VERSION 5.7 ;
BUSBITCHARS "[]" ;
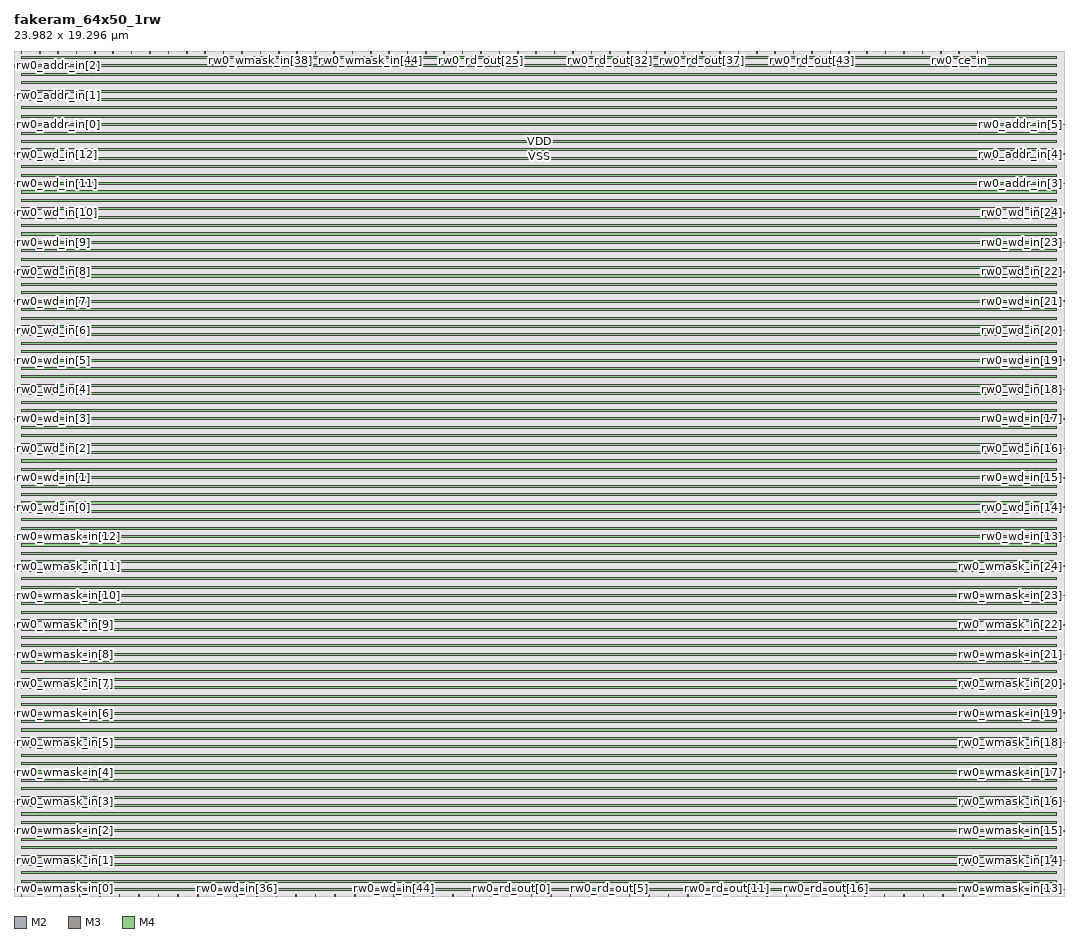
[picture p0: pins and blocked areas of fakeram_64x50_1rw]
MACRO fakeram_64x50_1rw
  FOREIGN fakeram_64x50_1rw 0 0 ;
  SYMMETRY X Y R90 ;
  SIZE 23.982 BY 19.296 ;
  CLASS BLOCK ;
  PIN rw0_wmask_in[0]
    DIRECTION INPUT ;
    USE SIGNAL ;
    SHAPE ABUTMENT ;
    PORT
      LAYER M2 ;
      RECT 0.000 0.138 0.036 0.150 ;
    END
  END rw0_wmask_in[0]
  PIN rw0_wmask_in[1]
    DIRECTION INPUT ;
    USE SIGNAL ;
    SHAPE ABUTMENT ;
    PORT
      LAYER M2 ;
      RECT 0.000 0.810 0.036 0.822 ;
    END
  END rw0_wmask_in[1]
  PIN rw0_wmask_in[2]
    DIRECTION INPUT ;
    USE SIGNAL ;
    SHAPE ABUTMENT ;
    PORT
      LAYER M2 ;
      RECT 0.000 1.482 0.036 1.494 ;
    END
  END rw0_wmask_in[2]
  PIN rw0_wmask_in[3]
    DIRECTION INPUT ;
    USE SIGNAL ;
    SHAPE ABUTMENT ;
    PORT
      LAYER M2 ;
      RECT 0.000 2.154 0.036 2.166 ;
    END
  END rw0_wmask_in[3]
  PIN rw0_wmask_in[4]
    DIRECTION INPUT ;
    USE SIGNAL ;
    SHAPE ABUTMENT ;
    PORT
      LAYER M2 ;
      RECT 0.000 2.826 0.036 2.838 ;
    END
  END rw0_wmask_in[4]
  PIN rw0_wmask_in[5]
    DIRECTION INPUT ;
    USE SIGNAL ;
    SHAPE ABUTMENT ;
    PORT
      LAYER M2 ;
      RECT 0.000 3.498 0.036 3.510 ;
    END
  END rw0_wmask_in[5]
  PIN rw0_wmask_in[6]
    DIRECTION INPUT ;
    USE SIGNAL ;
    SHAPE ABUTMENT ;
    PORT
      LAYER M2 ;
      RECT 0.000 4.170 0.036 4.182 ;
    END
  END rw0_wmask_in[6]
  PIN rw0_wmask_in[7]
    DIRECTION INPUT ;
    USE SIGNAL ;
    SHAPE ABUTMENT ;
    PORT
      LAYER M2 ;
      RECT 0.000 4.842 0.036 4.854 ;
    END
  END rw0_wmask_in[7]
  PIN rw0_wmask_in[8]
    DIRECTION INPUT ;
    USE SIGNAL ;
    SHAPE ABUTMENT ;
    PORT
      LAYER M2 ;
      RECT 0.000 5.514 0.036 5.526 ;
    END
  END rw0_wmask_in[8]
  PIN rw0_wmask_in[9]
    DIRECTION INPUT ;
    USE SIGNAL ;
    SHAPE ABUTMENT ;
    PORT
      LAYER M2 ;
      RECT 0.000 6.186 0.036 6.198 ;
    END
  END rw0_wmask_in[9]
  PIN rw0_wmask_in[10]
    DIRECTION INPUT ;
    USE SIGNAL ;
    SHAPE ABUTMENT ;
    PORT
      LAYER M2 ;
      RECT 0.000 6.858 0.036 6.870 ;
    END
  END rw0_wmask_in[10]
  PIN rw0_wmask_in[11]
    DIRECTION INPUT ;
    USE SIGNAL ;
    SHAPE ABUTMENT ;
    PORT
      LAYER M2 ;
      RECT 0.000 7.530 0.036 7.542 ;
    END
  END rw0_wmask_in[11]
  PIN rw0_wmask_in[12]
    DIRECTION INPUT ;
    USE SIGNAL ;
    SHAPE ABUTMENT ;
    PORT
      LAYER M2 ;
      RECT 0.000 8.202 0.036 8.214 ;
    END
  END rw0_wmask_in[12]
  PIN rw0_wmask_in[13]
    DIRECTION INPUT ;
    USE SIGNAL ;
    SHAPE ABUTMENT ;
    PORT
      LAYER M2 ;
      RECT 23.946 0.138 23.982 0.150 ;
    END
  END rw0_wmask_in[13]
  PIN rw0_wmask_in[14]
    DIRECTION INPUT ;
    USE SIGNAL ;
    SHAPE ABUTMENT ;
    PORT
      LAYER M2 ;
      RECT 23.946 0.810 23.982 0.822 ;
    END
  END rw0_wmask_in[14]
  PIN rw0_wmask_in[15]
    DIRECTION INPUT ;
    USE SIGNAL ;
    SHAPE ABUTMENT ;
    PORT
      LAYER M2 ;
      RECT 23.946 1.482 23.982 1.494 ;
    END
  END rw0_wmask_in[15]
  PIN rw0_wmask_in[16]
    DIRECTION INPUT ;
    USE SIGNAL ;
    SHAPE ABUTMENT ;
    PORT
      LAYER M2 ;
      RECT 23.946 2.154 23.982 2.166 ;
    END
  END rw0_wmask_in[16]
  PIN rw0_wmask_in[17]
    DIRECTION INPUT ;
    USE SIGNAL ;
    SHAPE ABUTMENT ;
    PORT
      LAYER M2 ;
      RECT 23.946 2.826 23.982 2.838 ;
    END
  END rw0_wmask_in[17]
  PIN rw0_wmask_in[18]
    DIRECTION INPUT ;
    USE SIGNAL ;
    SHAPE ABUTMENT ;
    PORT
      LAYER M2 ;
      RECT 23.946 3.498 23.982 3.510 ;
    END
  END rw0_wmask_in[18]
  PIN rw0_wmask_in[19]
    DIRECTION INPUT ;
    USE SIGNAL ;
    SHAPE ABUTMENT ;
    PORT
      LAYER M2 ;
      RECT 23.946 4.170 23.982 4.182 ;
    END
  END rw0_wmask_in[19]
  PIN rw0_wmask_in[20]
    DIRECTION INPUT ;
    USE SIGNAL ;
    SHAPE ABUTMENT ;
    PORT
      LAYER M2 ;
      RECT 23.946 4.842 23.982 4.854 ;
    END
  END rw0_wmask_in[20]
  PIN rw0_wmask_in[21]
    DIRECTION INPUT ;
    USE SIGNAL ;
    SHAPE ABUTMENT ;
    PORT
      LAYER M2 ;
      RECT 23.946 5.514 23.982 5.526 ;
    END
  END rw0_wmask_in[21]
  PIN rw0_wmask_in[22]
    DIRECTION INPUT ;
    USE SIGNAL ;
    SHAPE ABUTMENT ;
    PORT
      LAYER M2 ;
      RECT 23.946 6.186 23.982 6.198 ;
    END
  END rw0_wmask_in[22]
  PIN rw0_wmask_in[23]
    DIRECTION INPUT ;
    USE SIGNAL ;
    SHAPE ABUTMENT ;
    PORT
      LAYER M2 ;
      RECT 23.946 6.858 23.982 6.870 ;
    END
  END rw0_wmask_in[23]
  PIN rw0_wmask_in[24]
    DIRECTION INPUT ;
    USE SIGNAL ;
    SHAPE ABUTMENT ;
    PORT
      LAYER M2 ;
      RECT 23.946 7.530 23.982 7.542 ;
    END
  END rw0_wmask_in[24]
  PIN rw0_wmask_in[25]
    DIRECTION INPUT ;
    USE SIGNAL ;
    SHAPE ABUTMENT ;
    PORT
      LAYER M3 ;
      RECT 0.161 19.254 0.175 19.296 ;
    END
  END rw0_wmask_in[25]
  PIN rw0_wmask_in[26]
    DIRECTION INPUT ;
    USE SIGNAL ;
    SHAPE ABUTMENT ;
    PORT
      LAYER M3 ;
      RECT 0.581 19.254 0.595 19.296 ;
    END
  END rw0_wmask_in[26]
  PIN rw0_wmask_in[27]
    DIRECTION INPUT ;
    USE SIGNAL ;
    SHAPE ABUTMENT ;
    PORT
      LAYER M3 ;
      RECT 1.001 19.254 1.015 19.296 ;
    END
  END rw0_wmask_in[27]
  PIN rw0_wmask_in[28]
    DIRECTION INPUT ;
    USE SIGNAL ;
    SHAPE ABUTMENT ;
    PORT
      LAYER M3 ;
      RECT 1.421 19.254 1.435 19.296 ;
    END
  END rw0_wmask_in[28]
  PIN rw0_wmask_in[29]
    DIRECTION INPUT ;
    USE SIGNAL ;
    SHAPE ABUTMENT ;
    PORT
      LAYER M3 ;
      RECT 1.841 19.254 1.855 19.296 ;
    END
  END rw0_wmask_in[29]
  PIN rw0_wmask_in[30]
    DIRECTION INPUT ;
    USE SIGNAL ;
    SHAPE ABUTMENT ;
    PORT
      LAYER M3 ;
      RECT 2.261 19.254 2.275 19.296 ;
    END
  END rw0_wmask_in[30]
  PIN rw0_wmask_in[31]
    DIRECTION INPUT ;
    USE SIGNAL ;
    SHAPE ABUTMENT ;
    PORT
      LAYER M3 ;
      RECT 2.681 19.254 2.695 19.296 ;
    END
  END rw0_wmask_in[31]
  PIN rw0_wmask_in[32]
    DIRECTION INPUT ;
    USE SIGNAL ;
    SHAPE ABUTMENT ;
    PORT
      LAYER M3 ;
      RECT 3.101 19.254 3.115 19.296 ;
    END
  END rw0_wmask_in[32]
  PIN rw0_wmask_in[33]
    DIRECTION INPUT ;
    USE SIGNAL ;
    SHAPE ABUTMENT ;
    PORT
      LAYER M3 ;
      RECT 3.521 19.254 3.535 19.296 ;
    END
  END rw0_wmask_in[33]
  PIN rw0_wmask_in[34]
    DIRECTION INPUT ;
    USE SIGNAL ;
    SHAPE ABUTMENT ;
    PORT
      LAYER M3 ;
      RECT 3.941 19.254 3.955 19.296 ;
    END
  END rw0_wmask_in[34]
  PIN rw0_wmask_in[35]
    DIRECTION INPUT ;
    USE SIGNAL ;
    SHAPE ABUTMENT ;
    PORT
      LAYER M3 ;
      RECT 4.361 19.254 4.375 19.296 ;
    END
  END rw0_wmask_in[35]
  PIN rw0_wmask_in[36]
    DIRECTION INPUT ;
    USE SIGNAL ;
    SHAPE ABUTMENT ;
    PORT
      LAYER M3 ;
      RECT 4.781 19.254 4.795 19.296 ;
    END
  END rw0_wmask_in[36]
  PIN rw0_wmask_in[37]
    DIRECTION INPUT ;
    USE SIGNAL ;
    SHAPE ABUTMENT ;
    PORT
      LAYER M3 ;
      RECT 5.201 19.254 5.215 19.296 ;
    END
  END rw0_wmask_in[37]
  PIN rw0_wmask_in[38]
    DIRECTION INPUT ;
    USE SIGNAL ;
    SHAPE ABUTMENT ;
    PORT
      LAYER M3 ;
      RECT 5.621 19.254 5.635 19.296 ;
    END
  END rw0_wmask_in[38]
  PIN rw0_wmask_in[39]
    DIRECTION INPUT ;
    USE SIGNAL ;
    SHAPE ABUTMENT ;
    PORT
      LAYER M3 ;
      RECT 6.041 19.254 6.055 19.296 ;
    END
  END rw0_wmask_in[39]
  PIN rw0_wmask_in[40]
    DIRECTION INPUT ;
    USE SIGNAL ;
    SHAPE ABUTMENT ;
    PORT
      LAYER M3 ;
      RECT 6.461 19.254 6.475 19.296 ;
    END
  END rw0_wmask_in[40]
  PIN rw0_wmask_in[41]
    DIRECTION INPUT ;
    USE SIGNAL ;
    SHAPE ABUTMENT ;
    PORT
      LAYER M3 ;
      RECT 6.881 19.254 6.895 19.296 ;
    END
  END rw0_wmask_in[41]
  PIN rw0_wmask_in[42]
    DIRECTION INPUT ;
    USE SIGNAL ;
    SHAPE ABUTMENT ;
    PORT
      LAYER M3 ;
      RECT 7.301 19.254 7.315 19.296 ;
    END
  END rw0_wmask_in[42]
  PIN rw0_wmask_in[43]
    DIRECTION INPUT ;
    USE SIGNAL ;
    SHAPE ABUTMENT ;
    PORT
      LAYER M3 ;
      RECT 7.721 19.254 7.735 19.296 ;
    END
  END rw0_wmask_in[43]
  PIN rw0_wmask_in[44]
    DIRECTION INPUT ;
    USE SIGNAL ;
    SHAPE ABUTMENT ;
    PORT
      LAYER M3 ;
      RECT 8.141 19.254 8.155 19.296 ;
    END
  END rw0_wmask_in[44]
  PIN rw0_wmask_in[45]
    DIRECTION INPUT ;
    USE SIGNAL ;
    SHAPE ABUTMENT ;
    PORT
      LAYER M3 ;
      RECT 8.561 19.254 8.575 19.296 ;
    END
  END rw0_wmask_in[45]
  PIN rw0_wmask_in[46]
    DIRECTION INPUT ;
    USE SIGNAL ;
    SHAPE ABUTMENT ;
    PORT
      LAYER M3 ;
      RECT 8.981 19.254 8.995 19.296 ;
    END
  END rw0_wmask_in[46]
  PIN rw0_wmask_in[47]
    DIRECTION INPUT ;
    USE SIGNAL ;
    SHAPE ABUTMENT ;
    PORT
      LAYER M3 ;
      RECT 9.401 19.254 9.415 19.296 ;
    END
  END rw0_wmask_in[47]
  PIN rw0_wmask_in[48]
    DIRECTION INPUT ;
    USE SIGNAL ;
    SHAPE ABUTMENT ;
    PORT
      LAYER M3 ;
      RECT 9.821 19.254 9.835 19.296 ;
    END
  END rw0_wmask_in[48]
  PIN rw0_wmask_in[49]
    DIRECTION INPUT ;
    USE SIGNAL ;
    SHAPE ABUTMENT ;
    PORT
      LAYER M3 ;
      RECT 10.241 19.254 10.255 19.296 ;
    END
  END rw0_wmask_in[49]
  PIN rw0_wd_in[0]
    DIRECTION INPUT ;
    USE SIGNAL ;
    SHAPE ABUTMENT ;
    PORT
      LAYER M2 ;
      RECT 0.000 8.874 0.036 8.886 ;
    END
  END rw0_wd_in[0]
  PIN rw0_wd_in[1]
    DIRECTION INPUT ;
    USE SIGNAL ;
    SHAPE ABUTMENT ;
    PORT
      LAYER M2 ;
      RECT 0.000 9.546 0.036 9.558 ;
    END
  END rw0_wd_in[1]
  PIN rw0_wd_in[2]
    DIRECTION INPUT ;
    USE SIGNAL ;
    SHAPE ABUTMENT ;
    PORT
      LAYER M2 ;
      RECT 0.000 10.218 0.036 10.230 ;
    END
  END rw0_wd_in[2]
  PIN rw0_wd_in[3]
    DIRECTION INPUT ;
    USE SIGNAL ;
    SHAPE ABUTMENT ;
    PORT
      LAYER M2 ;
      RECT 0.000 10.890 0.036 10.902 ;
    END
  END rw0_wd_in[3]
  PIN rw0_wd_in[4]
    DIRECTION INPUT ;
    USE SIGNAL ;
    SHAPE ABUTMENT ;
    PORT
      LAYER M2 ;
      RECT 0.000 11.562 0.036 11.574 ;
    END
  END rw0_wd_in[4]
  PIN rw0_wd_in[5]
    DIRECTION INPUT ;
    USE SIGNAL ;
    SHAPE ABUTMENT ;
    PORT
      LAYER M2 ;
      RECT 0.000 12.234 0.036 12.246 ;
    END
  END rw0_wd_in[5]
  PIN rw0_wd_in[6]
    DIRECTION INPUT ;
    USE SIGNAL ;
    SHAPE ABUTMENT ;
    PORT
      LAYER M2 ;
      RECT 0.000 12.906 0.036 12.918 ;
    END
  END rw0_wd_in[6]
  PIN rw0_wd_in[7]
    DIRECTION INPUT ;
    USE SIGNAL ;
    SHAPE ABUTMENT ;
    PORT
      LAYER M2 ;
      RECT 0.000 13.578 0.036 13.590 ;
    END
  END rw0_wd_in[7]
  PIN rw0_wd_in[8]
    DIRECTION INPUT ;
    USE SIGNAL ;
    SHAPE ABUTMENT ;
    PORT
      LAYER M2 ;
      RECT 0.000 14.250 0.036 14.262 ;
    END
  END rw0_wd_in[8]
  PIN rw0_wd_in[9]
    DIRECTION INPUT ;
    USE SIGNAL ;
    SHAPE ABUTMENT ;
    PORT
      LAYER M2 ;
      RECT 0.000 14.922 0.036 14.934 ;
    END
  END rw0_wd_in[9]
  PIN rw0_wd_in[10]
    DIRECTION INPUT ;
    USE SIGNAL ;
    SHAPE ABUTMENT ;
    PORT
      LAYER M2 ;
      RECT 0.000 15.594 0.036 15.606 ;
    END
  END rw0_wd_in[10]
  PIN rw0_wd_in[11]
    DIRECTION INPUT ;
    USE SIGNAL ;
    SHAPE ABUTMENT ;
    PORT
      LAYER M2 ;
      RECT 0.000 16.266 0.036 16.278 ;
    END
  END rw0_wd_in[11]
  PIN rw0_wd_in[12]
    DIRECTION INPUT ;
    USE SIGNAL ;
    SHAPE ABUTMENT ;
    PORT
      LAYER M2 ;
      RECT 0.000 16.938 0.036 16.950 ;
    END
  END rw0_wd_in[12]
  PIN rw0_wd_in[13]
    DIRECTION INPUT ;
    USE SIGNAL ;
    SHAPE ABUTMENT ;
    PORT
      LAYER M2 ;
      RECT 23.946 8.202 23.982 8.214 ;
    END
  END rw0_wd_in[13]
  PIN rw0_wd_in[14]
    DIRECTION INPUT ;
    USE SIGNAL ;
    SHAPE ABUTMENT ;
    PORT
      LAYER M2 ;
      RECT 23.946 8.874 23.982 8.886 ;
    END
  END rw0_wd_in[14]
  PIN rw0_wd_in[15]
    DIRECTION INPUT ;
    USE SIGNAL ;
    SHAPE ABUTMENT ;
    PORT
      LAYER M2 ;
      RECT 23.946 9.546 23.982 9.558 ;
    END
  END rw0_wd_in[15]
  PIN rw0_wd_in[16]
    DIRECTION INPUT ;
    USE SIGNAL ;
    SHAPE ABUTMENT ;
    PORT
      LAYER M2 ;
      RECT 23.946 10.218 23.982 10.230 ;
    END
  END rw0_wd_in[16]
  PIN rw0_wd_in[17]
    DIRECTION INPUT ;
    USE SIGNAL ;
    SHAPE ABUTMENT ;
    PORT
      LAYER M2 ;
      RECT 23.946 10.890 23.982 10.902 ;
    END
  END rw0_wd_in[17]
  PIN rw0_wd_in[18]
    DIRECTION INPUT ;
    USE SIGNAL ;
    SHAPE ABUTMENT ;
    PORT
      LAYER M2 ;
      RECT 23.946 11.562 23.982 11.574 ;
    END
  END rw0_wd_in[18]
  PIN rw0_wd_in[19]
    DIRECTION INPUT ;
    USE SIGNAL ;
    SHAPE ABUTMENT ;
    PORT
      LAYER M2 ;
      RECT 23.946 12.234 23.982 12.246 ;
    END
  END rw0_wd_in[19]
  PIN rw0_wd_in[20]
    DIRECTION INPUT ;
    USE SIGNAL ;
    SHAPE ABUTMENT ;
    PORT
      LAYER M2 ;
      RECT 23.946 12.906 23.982 12.918 ;
    END
  END rw0_wd_in[20]
  PIN rw0_wd_in[21]
    DIRECTION INPUT ;
    USE SIGNAL ;
    SHAPE ABUTMENT ;
    PORT
      LAYER M2 ;
      RECT 23.946 13.578 23.982 13.590 ;
    END
  END rw0_wd_in[21]
  PIN rw0_wd_in[22]
    DIRECTION INPUT ;
    USE SIGNAL ;
    SHAPE ABUTMENT ;
    PORT
      LAYER M2 ;
      RECT 23.946 14.250 23.982 14.262 ;
    END
  END rw0_wd_in[22]
  PIN rw0_wd_in[23]
    DIRECTION INPUT ;
    USE SIGNAL ;
    SHAPE ABUTMENT ;
    PORT
      LAYER M2 ;
      RECT 23.946 14.922 23.982 14.934 ;
    END
  END rw0_wd_in[23]
  PIN rw0_wd_in[24]
    DIRECTION INPUT ;
    USE SIGNAL ;
    SHAPE ABUTMENT ;
    PORT
      LAYER M2 ;
      RECT 23.946 15.594 23.982 15.606 ;
    END
  END rw0_wd_in[24]
  PIN rw0_wd_in[25]
    DIRECTION INPUT ;
    USE SIGNAL ;
    SHAPE ABUTMENT ;
    PORT
      LAYER M3 ;
      RECT 0.161 0.000 0.175 0.042 ;
    END
  END rw0_wd_in[25]
  PIN rw0_wd_in[26]
    DIRECTION INPUT ;
    USE SIGNAL ;
    SHAPE ABUTMENT ;
    PORT
      LAYER M3 ;
      RECT 0.609 0.000 0.623 0.042 ;
    END
  END rw0_wd_in[26]
  PIN rw0_wd_in[27]
    DIRECTION INPUT ;
    USE SIGNAL ;
    SHAPE ABUTMENT ;
    PORT
      LAYER M3 ;
      RECT 1.057 0.000 1.071 0.042 ;
    END
  END rw0_wd_in[27]
  PIN rw0_wd_in[28]
    DIRECTION INPUT ;
    USE SIGNAL ;
    SHAPE ABUTMENT ;
    PORT
      LAYER M3 ;
      RECT 1.505 0.000 1.519 0.042 ;
    END
  END rw0_wd_in[28]
  PIN rw0_wd_in[29]
    DIRECTION INPUT ;
    USE SIGNAL ;
    SHAPE ABUTMENT ;
    PORT
      LAYER M3 ;
      RECT 1.953 0.000 1.967 0.042 ;
    END
  END rw0_wd_in[29]
  PIN rw0_wd_in[30]
    DIRECTION INPUT ;
    USE SIGNAL ;
    SHAPE ABUTMENT ;
    PORT
      LAYER M3 ;
      RECT 2.401 0.000 2.415 0.042 ;
    END
  END rw0_wd_in[30]
  PIN rw0_wd_in[31]
    DIRECTION INPUT ;
    USE SIGNAL ;
    SHAPE ABUTMENT ;
    PORT
      LAYER M3 ;
      RECT 2.849 0.000 2.863 0.042 ;
    END
  END rw0_wd_in[31]
  PIN rw0_wd_in[32]
    DIRECTION INPUT ;
    USE SIGNAL ;
    SHAPE ABUTMENT ;
    PORT
      LAYER M3 ;
      RECT 3.297 0.000 3.311 0.042 ;
    END
  END rw0_wd_in[32]
  PIN rw0_wd_in[33]
    DIRECTION INPUT ;
    USE SIGNAL ;
    SHAPE ABUTMENT ;
    PORT
      LAYER M3 ;
      RECT 3.745 0.000 3.759 0.042 ;
    END
  END rw0_wd_in[33]
  PIN rw0_wd_in[34]
    DIRECTION INPUT ;
    USE SIGNAL ;
    SHAPE ABUTMENT ;
    PORT
      LAYER M3 ;
      RECT 4.193 0.000 4.207 0.042 ;
    END
  END rw0_wd_in[34]
  PIN rw0_wd_in[35]
    DIRECTION INPUT ;
    USE SIGNAL ;
    SHAPE ABUTMENT ;
    PORT
      LAYER M3 ;
      RECT 4.641 0.000 4.655 0.042 ;
    END
  END rw0_wd_in[35]
  PIN rw0_wd_in[36]
    DIRECTION INPUT ;
    USE SIGNAL ;
    SHAPE ABUTMENT ;
    PORT
      LAYER M3 ;
      RECT 5.089 0.000 5.103 0.042 ;
    END
  END rw0_wd_in[36]
  PIN rw0_wd_in[37]
    DIRECTION INPUT ;
    USE SIGNAL ;
    SHAPE ABUTMENT ;
    PORT
      LAYER M3 ;
      RECT 5.537 0.000 5.551 0.042 ;
    END
  END rw0_wd_in[37]
  PIN rw0_wd_in[38]
    DIRECTION INPUT ;
    USE SIGNAL ;
    SHAPE ABUTMENT ;
    PORT
      LAYER M3 ;
      RECT 5.985 0.000 5.999 0.042 ;
    END
  END rw0_wd_in[38]
  PIN rw0_wd_in[39]
    DIRECTION INPUT ;
    USE SIGNAL ;
    SHAPE ABUTMENT ;
    PORT
      LAYER M3 ;
      RECT 6.433 0.000 6.447 0.042 ;
    END
  END rw0_wd_in[39]
  PIN rw0_wd_in[40]
    DIRECTION INPUT ;
    USE SIGNAL ;
    SHAPE ABUTMENT ;
    PORT
      LAYER M3 ;
      RECT 6.881 0.000 6.895 0.042 ;
    END
  END rw0_wd_in[40]
  PIN rw0_wd_in[41]
    DIRECTION INPUT ;
    USE SIGNAL ;
    SHAPE ABUTMENT ;
    PORT
      LAYER M3 ;
      RECT 7.329 0.000 7.343 0.042 ;
    END
  END rw0_wd_in[41]
  PIN rw0_wd_in[42]
    DIRECTION INPUT ;
    USE SIGNAL ;
    SHAPE ABUTMENT ;
    PORT
      LAYER M3 ;
      RECT 7.777 0.000 7.791 0.042 ;
    END
  END rw0_wd_in[42]
  PIN rw0_wd_in[43]
    DIRECTION INPUT ;
    USE SIGNAL ;
    SHAPE ABUTMENT ;
    PORT
      LAYER M3 ;
      RECT 8.225 0.000 8.239 0.042 ;
    END
  END rw0_wd_in[43]
  PIN rw0_wd_in[44]
    DIRECTION INPUT ;
    USE SIGNAL ;
    SHAPE ABUTMENT ;
    PORT
      LAYER M3 ;
      RECT 8.673 0.000 8.687 0.042 ;
    END
  END rw0_wd_in[44]
  PIN rw0_wd_in[45]
    DIRECTION INPUT ;
    USE SIGNAL ;
    SHAPE ABUTMENT ;
    PORT
      LAYER M3 ;
      RECT 9.121 0.000 9.135 0.042 ;
    END
  END rw0_wd_in[45]
  PIN rw0_wd_in[46]
    DIRECTION INPUT ;
    USE SIGNAL ;
    SHAPE ABUTMENT ;
    PORT
      LAYER M3 ;
      RECT 9.569 0.000 9.583 0.042 ;
    END
  END rw0_wd_in[46]
  PIN rw0_wd_in[47]
    DIRECTION INPUT ;
    USE SIGNAL ;
    SHAPE ABUTMENT ;
    PORT
      LAYER M3 ;
      RECT 10.017 0.000 10.031 0.042 ;
    END
  END rw0_wd_in[47]
  PIN rw0_wd_in[48]
    DIRECTION INPUT ;
    USE SIGNAL ;
    SHAPE ABUTMENT ;
    PORT
      LAYER M3 ;
      RECT 10.465 0.000 10.479 0.042 ;
    END
  END rw0_wd_in[48]
  PIN rw0_wd_in[49]
    DIRECTION INPUT ;
    USE SIGNAL ;
    SHAPE ABUTMENT ;
    PORT
      LAYER M3 ;
      RECT 10.913 0.000 10.927 0.042 ;
    END
  END rw0_wd_in[49]
  PIN rw0_rd_out[0]
    DIRECTION OUTPUT ;
    USE SIGNAL ;
    SHAPE ABUTMENT ;
    PORT
      LAYER M3 ;
      RECT 11.361 0.000 11.375 0.042 ;
    END
  END rw0_rd_out[0]
  PIN rw0_rd_out[1]
    DIRECTION OUTPUT ;
    USE SIGNAL ;
    SHAPE ABUTMENT ;
    PORT
      LAYER M3 ;
      RECT 11.809 0.000 11.823 0.042 ;
    END
  END rw0_rd_out[1]
  PIN rw0_rd_out[2]
    DIRECTION OUTPUT ;
    USE SIGNAL ;
    SHAPE ABUTMENT ;
    PORT
      LAYER M3 ;
      RECT 12.257 0.000 12.271 0.042 ;
    END
  END rw0_rd_out[2]
  PIN rw0_rd_out[3]
    DIRECTION OUTPUT ;
    USE SIGNAL ;
    SHAPE ABUTMENT ;
    PORT
      LAYER M3 ;
      RECT 12.705 0.000 12.719 0.042 ;
    END
  END rw0_rd_out[3]
  PIN rw0_rd_out[4]
    DIRECTION OUTPUT ;
    USE SIGNAL ;
    SHAPE ABUTMENT ;
    PORT
      LAYER M3 ;
      RECT 13.153 0.000 13.167 0.042 ;
    END
  END rw0_rd_out[4]
  PIN rw0_rd_out[5]
    DIRECTION OUTPUT ;
    USE SIGNAL ;
    SHAPE ABUTMENT ;
    PORT
      LAYER M3 ;
      RECT 13.601 0.000 13.615 0.042 ;
    END
  END rw0_rd_out[5]
  PIN rw0_rd_out[6]
    DIRECTION OUTPUT ;
    USE SIGNAL ;
    SHAPE ABUTMENT ;
    PORT
      LAYER M3 ;
      RECT 14.049 0.000 14.063 0.042 ;
    END
  END rw0_rd_out[6]
  PIN rw0_rd_out[7]
    DIRECTION OUTPUT ;
    USE SIGNAL ;
    SHAPE ABUTMENT ;
    PORT
      LAYER M3 ;
      RECT 14.497 0.000 14.511 0.042 ;
    END
  END rw0_rd_out[7]
  PIN rw0_rd_out[8]
    DIRECTION OUTPUT ;
    USE SIGNAL ;
    SHAPE ABUTMENT ;
    PORT
      LAYER M3 ;
      RECT 14.945 0.000 14.959 0.042 ;
    END
  END rw0_rd_out[8]
  PIN rw0_rd_out[9]
    DIRECTION OUTPUT ;
    USE SIGNAL ;
    SHAPE ABUTMENT ;
    PORT
      LAYER M3 ;
      RECT 15.393 0.000 15.407 0.042 ;
    END
  END rw0_rd_out[9]
  PIN rw0_rd_out[10]
    DIRECTION OUTPUT ;
    USE SIGNAL ;
    SHAPE ABUTMENT ;
    PORT
      LAYER M3 ;
      RECT 15.841 0.000 15.855 0.042 ;
    END
  END rw0_rd_out[10]
  PIN rw0_rd_out[11]
    DIRECTION OUTPUT ;
    USE SIGNAL ;
    SHAPE ABUTMENT ;
    PORT
      LAYER M3 ;
      RECT 16.289 0.000 16.303 0.042 ;
    END
  END rw0_rd_out[11]
  PIN rw0_rd_out[12]
    DIRECTION OUTPUT ;
    USE SIGNAL ;
    SHAPE ABUTMENT ;
    PORT
      LAYER M3 ;
      RECT 16.737 0.000 16.751 0.042 ;
    END
  END rw0_rd_out[12]
  PIN rw0_rd_out[13]
    DIRECTION OUTPUT ;
    USE SIGNAL ;
    SHAPE ABUTMENT ;
    PORT
      LAYER M3 ;
      RECT 17.185 0.000 17.199 0.042 ;
    END
  END rw0_rd_out[13]
  PIN rw0_rd_out[14]
    DIRECTION OUTPUT ;
    USE SIGNAL ;
    SHAPE ABUTMENT ;
    PORT
      LAYER M3 ;
      RECT 17.633 0.000 17.647 0.042 ;
    END
  END rw0_rd_out[14]
  PIN rw0_rd_out[15]
    DIRECTION OUTPUT ;
    USE SIGNAL ;
    SHAPE ABUTMENT ;
    PORT
      LAYER M3 ;
      RECT 18.081 0.000 18.095 0.042 ;
    END
  END rw0_rd_out[15]
  PIN rw0_rd_out[16]
    DIRECTION OUTPUT ;
    USE SIGNAL ;
    SHAPE ABUTMENT ;
    PORT
      LAYER M3 ;
      RECT 18.529 0.000 18.543 0.042 ;
    END
  END rw0_rd_out[16]
  PIN rw0_rd_out[17]
    DIRECTION OUTPUT ;
    USE SIGNAL ;
    SHAPE ABUTMENT ;
    PORT
      LAYER M3 ;
      RECT 18.977 0.000 18.991 0.042 ;
    END
  END rw0_rd_out[17]
  PIN rw0_rd_out[18]
    DIRECTION OUTPUT ;
    USE SIGNAL ;
    SHAPE ABUTMENT ;
    PORT
      LAYER M3 ;
      RECT 19.425 0.000 19.439 0.042 ;
    END
  END rw0_rd_out[18]
  PIN rw0_rd_out[19]
    DIRECTION OUTPUT ;
    USE SIGNAL ;
    SHAPE ABUTMENT ;
    PORT
      LAYER M3 ;
      RECT 19.873 0.000 19.887 0.042 ;
    END
  END rw0_rd_out[19]
  PIN rw0_rd_out[20]
    DIRECTION OUTPUT ;
    USE SIGNAL ;
    SHAPE ABUTMENT ;
    PORT
      LAYER M3 ;
      RECT 20.321 0.000 20.335 0.042 ;
    END
  END rw0_rd_out[20]
  PIN rw0_rd_out[21]
    DIRECTION OUTPUT ;
    USE SIGNAL ;
    SHAPE ABUTMENT ;
    PORT
      LAYER M3 ;
      RECT 20.769 0.000 20.783 0.042 ;
    END
  END rw0_rd_out[21]
  PIN rw0_rd_out[22]
    DIRECTION OUTPUT ;
    USE SIGNAL ;
    SHAPE ABUTMENT ;
    PORT
      LAYER M3 ;
      RECT 21.217 0.000 21.231 0.042 ;
    END
  END rw0_rd_out[22]
  PIN rw0_rd_out[23]
    DIRECTION OUTPUT ;
    USE SIGNAL ;
    SHAPE ABUTMENT ;
    PORT
      LAYER M3 ;
      RECT 21.665 0.000 21.679 0.042 ;
    END
  END rw0_rd_out[23]
  PIN rw0_rd_out[24]
    DIRECTION OUTPUT ;
    USE SIGNAL ;
    SHAPE ABUTMENT ;
    PORT
      LAYER M3 ;
      RECT 22.113 0.000 22.127 0.042 ;
    END
  END rw0_rd_out[24]
  PIN rw0_rd_out[25]
    DIRECTION OUTPUT ;
    USE SIGNAL ;
    SHAPE ABUTMENT ;
    PORT
      LAYER M3 ;
      RECT 10.661 19.254 10.675 19.296 ;
    END
  END rw0_rd_out[25]
  PIN rw0_rd_out[26]
    DIRECTION OUTPUT ;
    USE SIGNAL ;
    SHAPE ABUTMENT ;
    PORT
      LAYER M3 ;
      RECT 11.081 19.254 11.095 19.296 ;
    END
  END rw0_rd_out[26]
  PIN rw0_rd_out[27]
    DIRECTION OUTPUT ;
    USE SIGNAL ;
    SHAPE ABUTMENT ;
    PORT
      LAYER M3 ;
      RECT 11.501 19.254 11.515 19.296 ;
    END
  END rw0_rd_out[27]
  PIN rw0_rd_out[28]
    DIRECTION OUTPUT ;
    USE SIGNAL ;
    SHAPE ABUTMENT ;
    PORT
      LAYER M3 ;
      RECT 11.921 19.254 11.935 19.296 ;
    END
  END rw0_rd_out[28]
  PIN rw0_rd_out[29]
    DIRECTION OUTPUT ;
    USE SIGNAL ;
    SHAPE ABUTMENT ;
    PORT
      LAYER M3 ;
      RECT 12.341 19.254 12.355 19.296 ;
    END
  END rw0_rd_out[29]
  PIN rw0_rd_out[30]
    DIRECTION OUTPUT ;
    USE SIGNAL ;
    SHAPE ABUTMENT ;
    PORT
      LAYER M3 ;
      RECT 12.761 19.254 12.775 19.296 ;
    END
  END rw0_rd_out[30]
  PIN rw0_rd_out[31]
    DIRECTION OUTPUT ;
    USE SIGNAL ;
    SHAPE ABUTMENT ;
    PORT
      LAYER M3 ;
      RECT 13.181 19.254 13.195 19.296 ;
    END
  END rw0_rd_out[31]
  PIN rw0_rd_out[32]
    DIRECTION OUTPUT ;
    USE SIGNAL ;
    SHAPE ABUTMENT ;
    PORT
      LAYER M3 ;
      RECT 13.601 19.254 13.615 19.296 ;
    END
  END rw0_rd_out[32]
  PIN rw0_rd_out[33]
    DIRECTION OUTPUT ;
    USE SIGNAL ;
    SHAPE ABUTMENT ;
    PORT
      LAYER M3 ;
      RECT 14.021 19.254 14.035 19.296 ;
    END
  END rw0_rd_out[33]
  PIN rw0_rd_out[34]
    DIRECTION OUTPUT ;
    USE SIGNAL ;
    SHAPE ABUTMENT ;
    PORT
      LAYER M3 ;
      RECT 14.441 19.254 14.455 19.296 ;
    END
  END rw0_rd_out[34]
  PIN rw0_rd_out[35]
    DIRECTION OUTPUT ;
    USE SIGNAL ;
    SHAPE ABUTMENT ;
    PORT
      LAYER M3 ;
      RECT 14.861 19.254 14.875 19.296 ;
    END
  END rw0_rd_out[35]
  PIN rw0_rd_out[36]
    DIRECTION OUTPUT ;
    USE SIGNAL ;
    SHAPE ABUTMENT ;
    PORT
      LAYER M3 ;
      RECT 15.281 19.254 15.295 19.296 ;
    END
  END rw0_rd_out[36]
  PIN rw0_rd_out[37]
    DIRECTION OUTPUT ;
    USE SIGNAL ;
    SHAPE ABUTMENT ;
    PORT
      LAYER M3 ;
      RECT 15.701 19.254 15.715 19.296 ;
    END
  END rw0_rd_out[37]
  PIN rw0_rd_out[38]
    DIRECTION OUTPUT ;
    USE SIGNAL ;
    SHAPE ABUTMENT ;
    PORT
      LAYER M3 ;
      RECT 16.121 19.254 16.135 19.296 ;
    END
  END rw0_rd_out[38]
  PIN rw0_rd_out[39]
    DIRECTION OUTPUT ;
    USE SIGNAL ;
    SHAPE ABUTMENT ;
    PORT
      LAYER M3 ;
      RECT 16.541 19.254 16.555 19.296 ;
    END
  END rw0_rd_out[39]
  PIN rw0_rd_out[40]
    DIRECTION OUTPUT ;
    USE SIGNAL ;
    SHAPE ABUTMENT ;
    PORT
      LAYER M3 ;
      RECT 16.961 19.254 16.975 19.296 ;
    END
  END rw0_rd_out[40]
  PIN rw0_rd_out[41]
    DIRECTION OUTPUT ;
    USE SIGNAL ;
    SHAPE ABUTMENT ;
    PORT
      LAYER M3 ;
      RECT 17.381 19.254 17.395 19.296 ;
    END
  END rw0_rd_out[41]
  PIN rw0_rd_out[42]
    DIRECTION OUTPUT ;
    USE SIGNAL ;
    SHAPE ABUTMENT ;
    PORT
      LAYER M3 ;
      RECT 17.801 19.254 17.815 19.296 ;
    END
  END rw0_rd_out[42]
  PIN rw0_rd_out[43]
    DIRECTION OUTPUT ;
    USE SIGNAL ;
    SHAPE ABUTMENT ;
    PORT
      LAYER M3 ;
      RECT 18.221 19.254 18.235 19.296 ;
    END
  END rw0_rd_out[43]
  PIN rw0_rd_out[44]
    DIRECTION OUTPUT ;
    USE SIGNAL ;
    SHAPE ABUTMENT ;
    PORT
      LAYER M3 ;
      RECT 18.641 19.254 18.655 19.296 ;
    END
  END rw0_rd_out[44]
  PIN rw0_rd_out[45]
    DIRECTION OUTPUT ;
    USE SIGNAL ;
    SHAPE ABUTMENT ;
    PORT
      LAYER M3 ;
      RECT 19.061 19.254 19.075 19.296 ;
    END
  END rw0_rd_out[45]
  PIN rw0_rd_out[46]
    DIRECTION OUTPUT ;
    USE SIGNAL ;
    SHAPE ABUTMENT ;
    PORT
      LAYER M3 ;
      RECT 19.481 19.254 19.495 19.296 ;
    END
  END rw0_rd_out[46]
  PIN rw0_rd_out[47]
    DIRECTION OUTPUT ;
    USE SIGNAL ;
    SHAPE ABUTMENT ;
    PORT
      LAYER M3 ;
      RECT 19.901 19.254 19.915 19.296 ;
    END
  END rw0_rd_out[47]
  PIN rw0_rd_out[48]
    DIRECTION OUTPUT ;
    USE SIGNAL ;
    SHAPE ABUTMENT ;
    PORT
      LAYER M3 ;
      RECT 20.321 19.254 20.335 19.296 ;
    END
  END rw0_rd_out[48]
  PIN rw0_rd_out[49]
    DIRECTION OUTPUT ;
    USE SIGNAL ;
    SHAPE ABUTMENT ;
    PORT
      LAYER M3 ;
      RECT 20.741 19.254 20.755 19.296 ;
    END
  END rw0_rd_out[49]
  PIN rw0_addr_in[0]
    DIRECTION INPUT ;
    USE SIGNAL ;
    SHAPE ABUTMENT ;
    PORT
      LAYER M2 ;
      RECT 0.000 17.610 0.036 17.622 ;
    END
  END rw0_addr_in[0]
  PIN rw0_addr_in[1]
    DIRECTION INPUT ;
    USE SIGNAL ;
    SHAPE ABUTMENT ;
    PORT
      LAYER M2 ;
      RECT 0.000 18.282 0.036 18.294 ;
    END
  END rw0_addr_in[1]
  PIN rw0_addr_in[2]
    DIRECTION INPUT ;
    USE SIGNAL ;
    SHAPE ABUTMENT ;
    PORT
      LAYER M2 ;
      RECT 0.000 18.954 0.036 18.966 ;
    END
  END rw0_addr_in[2]
  PIN rw0_addr_in[3]
    DIRECTION INPUT ;
    USE SIGNAL ;
    SHAPE ABUTMENT ;
    PORT
      LAYER M2 ;
      RECT 23.946 16.266 23.982 16.278 ;
    END
  END rw0_addr_in[3]
  PIN rw0_addr_in[4]
    DIRECTION INPUT ;
    USE SIGNAL ;
    SHAPE ABUTMENT ;
    PORT
      LAYER M2 ;
      RECT 23.946 16.938 23.982 16.950 ;
    END
  END rw0_addr_in[4]
  PIN rw0_addr_in[5]
    DIRECTION INPUT ;
    USE SIGNAL ;
    SHAPE ABUTMENT ;
    PORT
      LAYER M2 ;
      RECT 23.946 17.610 23.982 17.622 ;
    END
  END rw0_addr_in[5]
  PIN rw0_we_in
    DIRECTION INPUT ;
    USE SIGNAL ;
    SHAPE ABUTMENT ;
    PORT
      LAYER M3 ;
      RECT 21.161 19.254 21.175 19.296 ;
    END
  END rw0_we_in
  PIN rw0_ce_in
    DIRECTION INPUT ;
    USE SIGNAL ;
    SHAPE ABUTMENT ;
    PORT
      LAYER M3 ;
      RECT 21.581 19.254 21.595 19.296 ;
    END
  END rw0_ce_in
  PIN rw0_clk
    DIRECTION INPUT ;
    USE SIGNAL ;
    SHAPE ABUTMENT ;
    PORT
      LAYER M3 ;
      RECT 22.001 19.254 22.015 19.296 ;
    END
  END rw0_clk
  PIN VSS
    DIRECTION INOUT ;
    USE GROUND ;
    PORT
      LAYER M4 ;
      RECT 0.168 0.120 23.814 0.168 ;
      RECT 0.168 0.504 23.814 0.552 ;
      RECT 0.168 0.888 23.814 0.936 ;
      RECT 0.168 1.272 23.814 1.320 ;
      RECT 0.168 1.656 23.814 1.704 ;
      RECT 0.168 2.040 23.814 2.088 ;
      RECT 0.168 2.424 23.814 2.472 ;
      RECT 0.168 2.808 23.814 2.856 ;
      RECT 0.168 3.192 23.814 3.240 ;
      RECT 0.168 3.576 23.814 3.624 ;
      RECT 0.168 3.960 23.814 4.008 ;
      RECT 0.168 4.344 23.814 4.392 ;
      RECT 0.168 4.728 23.814 4.776 ;
      RECT 0.168 5.112 23.814 5.160 ;
      RECT 0.168 5.496 23.814 5.544 ;
      RECT 0.168 5.880 23.814 5.928 ;
      RECT 0.168 6.264 23.814 6.312 ;
      RECT 0.168 6.648 23.814 6.696 ;
      RECT 0.168 7.032 23.814 7.080 ;
      RECT 0.168 7.416 23.814 7.464 ;
      RECT 0.168 7.800 23.814 7.848 ;
      RECT 0.168 8.184 23.814 8.232 ;
      RECT 0.168 8.568 23.814 8.616 ;
      RECT 0.168 8.952 23.814 9.000 ;
      RECT 0.168 9.336 23.814 9.384 ;
      RECT 0.168 9.720 23.814 9.768 ;
      RECT 0.168 10.104 23.814 10.152 ;
      RECT 0.168 10.488 23.814 10.536 ;
      RECT 0.168 10.872 23.814 10.920 ;
      RECT 0.168 11.256 23.814 11.304 ;
      RECT 0.168 11.640 23.814 11.688 ;
      RECT 0.168 12.024 23.814 12.072 ;
      RECT 0.168 12.408 23.814 12.456 ;
      RECT 0.168 12.792 23.814 12.840 ;
      RECT 0.168 13.176 23.814 13.224 ;
      RECT 0.168 13.560 23.814 13.608 ;
      RECT 0.168 13.944 23.814 13.992 ;
      RECT 0.168 14.328 23.814 14.376 ;
      RECT 0.168 14.712 23.814 14.760 ;
      RECT 0.168 15.096 23.814 15.144 ;
      RECT 0.168 15.480 23.814 15.528 ;
      RECT 0.168 15.864 23.814 15.912 ;
      RECT 0.168 16.248 23.814 16.296 ;
      RECT 0.168 16.632 23.814 16.680 ;
      RECT 0.168 17.016 23.814 17.064 ;
      RECT 0.168 17.400 23.814 17.448 ;
      RECT 0.168 17.784 23.814 17.832 ;
      RECT 0.168 18.168 23.814 18.216 ;
      RECT 0.168 18.552 23.814 18.600 ;
      RECT 0.168 18.936 23.814 18.984 ;
    END
  END VSS
  PIN VDD
    DIRECTION INOUT ;
    USE POWER ;
    PORT
      LAYER M4 ;
      RECT 0.168 0.312 23.814 0.360 ;
      RECT 0.168 0.696 23.814 0.744 ;
      RECT 0.168 1.080 23.814 1.128 ;
      RECT 0.168 1.464 23.814 1.512 ;
      RECT 0.168 1.848 23.814 1.896 ;
      RECT 0.168 2.232 23.814 2.280 ;
      RECT 0.168 2.616 23.814 2.664 ;
      RECT 0.168 3.000 23.814 3.048 ;
      RECT 0.168 3.384 23.814 3.432 ;
      RECT 0.168 3.768 23.814 3.816 ;
      RECT 0.168 4.152 23.814 4.200 ;
      RECT 0.168 4.536 23.814 4.584 ;
      RECT 0.168 4.920 23.814 4.968 ;
      RECT 0.168 5.304 23.814 5.352 ;
      RECT 0.168 5.688 23.814 5.736 ;
      RECT 0.168 6.072 23.814 6.120 ;
      RECT 0.168 6.456 23.814 6.504 ;
      RECT 0.168 6.840 23.814 6.888 ;
      RECT 0.168 7.224 23.814 7.272 ;
      RECT 0.168 7.608 23.814 7.656 ;
      RECT 0.168 7.992 23.814 8.040 ;
      RECT 0.168 8.376 23.814 8.424 ;
      RECT 0.168 8.760 23.814 8.808 ;
      RECT 0.168 9.144 23.814 9.192 ;
      RECT 0.168 9.528 23.814 9.576 ;
      RECT 0.168 9.912 23.814 9.960 ;
      RECT 0.168 10.296 23.814 10.344 ;
      RECT 0.168 10.680 23.814 10.728 ;
      RECT 0.168 11.064 23.814 11.112 ;
      RECT 0.168 11.448 23.814 11.496 ;
      RECT 0.168 11.832 23.814 11.880 ;
      RECT 0.168 12.216 23.814 12.264 ;
      RECT 0.168 12.600 23.814 12.648 ;
      RECT 0.168 12.984 23.814 13.032 ;
      RECT 0.168 13.368 23.814 13.416 ;
      RECT 0.168 13.752 23.814 13.800 ;
      RECT 0.168 14.136 23.814 14.184 ;
      RECT 0.168 14.520 23.814 14.568 ;
      RECT 0.168 14.904 23.814 14.952 ;
      RECT 0.168 15.288 23.814 15.336 ;
      RECT 0.168 15.672 23.814 15.720 ;
      RECT 0.168 16.056 23.814 16.104 ;
      RECT 0.168 16.440 23.814 16.488 ;
      RECT 0.168 16.824 23.814 16.872 ;
      RECT 0.168 17.208 23.814 17.256 ;
      RECT 0.168 17.592 23.814 17.640 ;
      RECT 0.168 17.976 23.814 18.024 ;
      RECT 0.168 18.360 23.814 18.408 ;
      RECT 0.168 18.744 23.814 18.792 ;
      RECT 0.168 19.128 23.814 19.176 ;
    END
  END VDD
  OBS
    LAYER M1 ;
    RECT 0 0 23.982 19.296 ;
    LAYER M2 ;
    RECT 0 0 23.982 19.296 ;
    LAYER M3 ;
    RECT 0 0 23.982 19.296 ;
    LAYER M4 ;
    RECT 0 0 23.982 19.296 ;
  END
END fakeram_64x50_1rw

END LIBRARY
